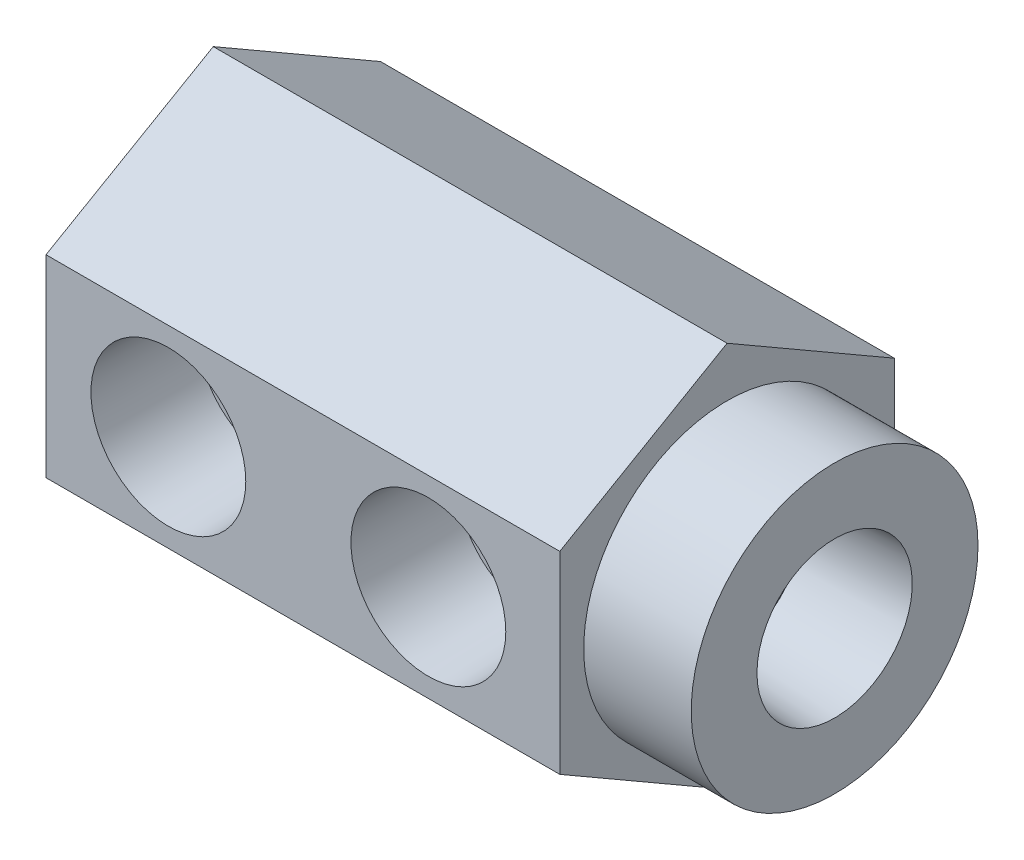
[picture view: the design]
ISO-10303-21;
HEADER;
FILE_DESCRIPTION(('STEP AP214'),'2;1');
FILE_NAME('part.step','',(''),(''),'','','');
FILE_SCHEMA(('AUTOMOTIVE_DESIGN { 1 0 10303 214 1 1 1 1 }'));
ENDSEC;
DATA;
#1=APPLICATION_CONTEXT('core data for automotive mechanical design processes');
#2=APPLICATION_PROTOCOL_DEFINITION('international standard','automotive_design',2000,#1);
#3=PRODUCT_CONTEXT('',#1,'mechanical');
#4=PRODUCT('Part','Part','',(#3));
#5=PRODUCT_RELATED_PRODUCT_CATEGORY('part','',(#4));
#6=PRODUCT_DEFINITION_FORMATION('','',#4);
#7=PRODUCT_DEFINITION_CONTEXT('part definition',#1,'design');
#8=PRODUCT_DEFINITION('design','',#6,#7);
#9=PRODUCT_DEFINITION_SHAPE('','',#8);
#10=(LENGTH_UNIT() NAMED_UNIT(*) SI_UNIT(.MILLI.,.METRE.));
#11=(NAMED_UNIT(*) PLANE_ANGLE_UNIT() SI_UNIT($,.RADIAN.));
#12=(NAMED_UNIT(*) SI_UNIT($,.STERADIAN.) SOLID_ANGLE_UNIT());
#13=UNCERTAINTY_MEASURE_WITH_UNIT(LENGTH_MEASURE(1.E-05),#10,'distance_accuracy_value','');
#14=(GEOMETRIC_REPRESENTATION_CONTEXT(3) GLOBAL_UNCERTAINTY_ASSIGNED_CONTEXT((#13)) GLOBAL_UNIT_ASSIGNED_CONTEXT((#10,
#11,#12)) REPRESENTATION_CONTEXT('',''));
#15=CARTESIAN_POINT('',(0.,0.,0.));
#16=DIRECTION('',(0.,0.,1.));
#17=DIRECTION('',(1.,0.,0.));
#18=AXIS2_PLACEMENT_3D('',#15,#16,#17);
#19=CARTESIAN_POINT('',(25.4,0.,0.));
#20=DIRECTION('',(1.,0.,0.));
#21=DIRECTION('',(0.,0.,-1.));
#22=AXIS2_PLACEMENT_3D('',#19,#20,#21);
#23=PLANE('',#22);
#24=DIRECTION('',(0.,0.,1.));
#25=VECTOR('',#24,1.);
#26=CARTESIAN_POINT('',(25.4,4.2164,11.1125));
#27=LINE('',#26,#25);
#28=CARTESIAN_POINT('',(25.4,4.2164,-1.14384635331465));
#29=VERTEX_POINT('',#28);
#30=CARTESIAN_POINT('',(25.4,4.2164,1.14384635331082));
#31=VERTEX_POINT('',#30);
#32=EDGE_CURVE('E247',#29,#31,#27,.T.);
#33=ORIENTED_EDGE('',*,*,#32,.F.);
#34=CARTESIAN_POINT('',(25.4,0.,0.));
#35=DIRECTION('',(-1.,0.,0.));
#36=DIRECTION('',(0.,0.,1.));
#37=AXIS2_PLACEMENT_3D('',#34,#35,#36);
#38=CIRCLE('',#37,4.36879999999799);
#39=EDGE_CURVE('E286',#31,#29,#38,.T.);
#40=ORIENTED_EDGE('',*,*,#39,.F.);
#41=EDGE_LOOP('',(#33,#40));
#42=FACE_BOUND('',#41,.T.);
#43=ADVANCED_FACE('F34',(#42),#23,.T.);
#44=CARTESIAN_POINT('',(41.275,0.,0.));
#45=DIRECTION('',(1.,0.,0.));
#46=DIRECTION('',(0.,0.,-1.));
#47=AXIS2_PLACEMENT_3D('',#44,#45,#46);
#48=PLANE('',#47);
#49=CARTESIAN_POINT('',(41.275,0.,0.));
#50=DIRECTION('',(1.,0.,0.));
#51=DIRECTION('',(0.,0.,-1.));
#52=AXIS2_PLACEMENT_3D('',#49,#50,#51);
#53=CIRCLE('',#52,9.525);
#54=CARTESIAN_POINT('',(41.275,0.,-9.525));
#55=VERTEX_POINT('',#54);
#56=EDGE_CURVE('E297',#55,#55,#53,.T.);
#57=ORIENTED_EDGE('',*,*,#56,.T.);
#58=EDGE_LOOP('',(#57));
#59=FACE_BOUND('',#58,.T.);
#60=CARTESIAN_POINT('',(41.275,0.,0.));
#61=DIRECTION('',(-1.,0.,0.));
#62=DIRECTION('',(0.,0.,1.));
#63=AXIS2_PLACEMENT_3D('',#60,#61,#62);
#64=CIRCLE('',#63,5.15886231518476);
#65=CARTESIAN_POINT('',(41.275,0.,5.15886231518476));
#66=VERTEX_POINT('',#65);
#67=EDGE_CURVE('E294',#66,#66,#64,.T.);
#68=ORIENTED_EDGE('',*,*,#67,.T.);
#69=EDGE_LOOP('',(#68));
#70=FACE_BOUND('',#69,.T.);
#71=ADVANCED_FACE('F320',(#59,#70),#48,.T.);
#72=CARTESIAN_POINT('',(34.13125,6.41580486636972,11.1125));
#73=DIRECTION('',(1.,0.,0.));
#74=DIRECTION('',(0.,0.,-1.));
#75=AXIS2_PLACEMENT_3D('',#72,#73,#74);
#76=PLANE('',#75);
#77=DIRECTION('',(0.,-0.5,0.866025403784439));
#78=VECTOR('',#77,1.);
#79=CARTESIAN_POINT('',(34.13125,12.8316097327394,0.));
#80=LINE('',#79,#78);
#81=CARTESIAN_POINT('',(34.13125,12.8316097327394,0.));
#82=VERTEX_POINT('',#81);
#83=CARTESIAN_POINT('',(34.13125,6.41580486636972,11.1125));
#84=VERTEX_POINT('',#83);
#85=EDGE_CURVE('E151',#82,#84,#80,.T.);
#86=ORIENTED_EDGE('',*,*,#85,.T.);
#87=DIRECTION('',(0.,-1.,0.));
#88=VECTOR('',#87,1.);
#89=CARTESIAN_POINT('',(34.13125,6.41580486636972,11.1125));
#90=LINE('',#89,#88);
#91=CARTESIAN_POINT('',(34.13125,-6.41580486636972,11.1125));
#92=VERTEX_POINT('',#91);
#93=EDGE_CURVE('E101',#84,#92,#90,.T.);
#94=ORIENTED_EDGE('',*,*,#93,.T.);
#95=DIRECTION('',(0.,-0.5,-0.866025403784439));
#96=VECTOR('',#95,1.);
#97=CARTESIAN_POINT('',(34.13125,-6.41580486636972,11.1125));
#98=LINE('',#97,#96);
#99=CARTESIAN_POINT('',(34.13125,-12.8316097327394,0.));
#100=VERTEX_POINT('',#99);
#101=EDGE_CURVE('E118',#92,#100,#98,.T.);
#102=ORIENTED_EDGE('',*,*,#101,.T.);
#103=DIRECTION('',(0.,0.5,-0.866025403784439));
#104=VECTOR('',#103,1.);
#105=CARTESIAN_POINT('',(34.13125,-12.8316097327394,0.));
#106=LINE('',#105,#104);
#107=CARTESIAN_POINT('',(34.13125,-6.41580486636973,-11.1125));
#108=VERTEX_POINT('',#107);
#109=EDGE_CURVE('E110',#100,#108,#106,.T.);
#110=ORIENTED_EDGE('',*,*,#109,.T.);
#111=DIRECTION('',(0.,1.,0.));
#112=VECTOR('',#111,1.);
#113=CARTESIAN_POINT('',(34.13125,-6.41580486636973,-11.1125));
#114=LINE('',#113,#112);
#115=CARTESIAN_POINT('',(34.13125,6.41580486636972,-11.1125));
#116=VERTEX_POINT('',#115);
#117=EDGE_CURVE('E115',#108,#116,#114,.T.);
#118=ORIENTED_EDGE('',*,*,#117,.T.);
#119=DIRECTION('',(0.,0.5,0.866025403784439));
#120=VECTOR('',#119,1.);
#121=CARTESIAN_POINT('',(34.13125,6.41580486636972,-11.1125));
#122=LINE('',#121,#120);
#123=EDGE_CURVE('E65',#116,#82,#122,.T.);
#124=ORIENTED_EDGE('',*,*,#123,.T.);
#125=EDGE_LOOP('',(#86,#94,#102,#110,#118,#124));
#126=FACE_BOUND('',#125,.T.);
#127=CARTESIAN_POINT('',(34.13125,0.,0.));
#128=DIRECTION('',(1.,0.,0.));
#129=DIRECTION('',(0.,0.,-1.));
#130=AXIS2_PLACEMENT_3D('',#127,#128,#129);
#131=CIRCLE('',#130,9.525);
#132=CARTESIAN_POINT('',(34.13125,0.,-9.525));
#133=VERTEX_POINT('',#132);
#134=EDGE_CURVE('E143',#133,#133,#131,.F.);
#135=ORIENTED_EDGE('',*,*,#134,.T.);
#136=EDGE_LOOP('',(#135));
#137=FACE_BOUND('',#136,.T.);
#138=ADVANCED_FACE('F112',(#126,#137),#76,.T.);
#139=CARTESIAN_POINT('',(34.13125,12.8316097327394,0.));
#140=DIRECTION('',(0.,-0.866025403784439,-0.5));
#141=DIRECTION('',(0.,0.5,-0.866025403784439));
#142=AXIS2_PLACEMENT_3D('',#139,#140,#141);
#143=PLANE('',#142);
#144=DIRECTION('',(0.,-0.5,0.866025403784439));
#145=VECTOR('',#144,1.);
#146=CARTESIAN_POINT('',(0.,12.8316097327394,0.));
#147=LINE('',#146,#145);
#148=CARTESIAN_POINT('',(0.,12.8316097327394,0.));
#149=VERTEX_POINT('',#148);
#150=CARTESIAN_POINT('',(0.,6.41580486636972,11.1125));
#151=VERTEX_POINT('',#150);
#152=EDGE_CURVE('E139',#149,#151,#147,.T.);
#153=ORIENTED_EDGE('',*,*,#152,.T.);
#154=DIRECTION('',(-1.,0.,0.));
#155=VECTOR('',#154,1.);
#156=CARTESIAN_POINT('',(34.13125,6.41580486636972,11.1125));
#157=LINE('',#156,#155);
#158=EDGE_CURVE('E158',#84,#151,#157,.T.);
#159=ORIENTED_EDGE('',*,*,#158,.F.);
#160=ORIENTED_EDGE('',*,*,#85,.F.);
#161=DIRECTION('',(-1.,0.,0.));
#162=VECTOR('',#161,1.);
#163=CARTESIAN_POINT('',(34.13125,12.8316097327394,0.));
#164=LINE('',#163,#162);
#165=EDGE_CURVE('E135',#82,#149,#164,.T.);
#166=ORIENTED_EDGE('',*,*,#165,.T.);
#167=EDGE_LOOP('',(#153,#159,#160,#166));
#168=FACE_BOUND('',#167,.T.);
#169=ADVANCED_FACE('F36',(#168),#143,.F.);
#170=CARTESIAN_POINT('',(34.13125,6.41580486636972,11.1125));
#171=DIRECTION('',(0.,0.,-1.));
#172=DIRECTION('',(0.,1.,0.));
#173=AXIS2_PLACEMENT_3D('',#170,#171,#172);
#174=PLANE('',#173);
#175=CARTESIAN_POINT('',(8.128,0.,11.1125));
#176=DIRECTION('',(0.,0.,1.));
#177=DIRECTION('',(1.,0.,0.));
#178=AXIS2_PLACEMENT_3D('',#175,#176,#177);
#179=CIRCLE('',#178,5.1435);
#180=CARTESIAN_POINT('',(13.2715,0.,11.1125));
#181=VERTEX_POINT('',#180);
#182=EDGE_CURVE('E562',#181,#181,#179,.T.);
#183=ORIENTED_EDGE('',*,*,#182,.F.);
#184=EDGE_LOOP('',(#183));
#185=FACE_BOUND('',#184,.T.);
#186=CARTESIAN_POINT('',(25.4,0.,11.1125));
#187=DIRECTION('',(0.,0.,1.));
#188=DIRECTION('',(1.,0.,0.));
#189=AXIS2_PLACEMENT_3D('',#186,#187,#188);
#190=CIRCLE('',#189,5.1435);
#191=CARTESIAN_POINT('',(30.5435,0.,11.1125));
#192=VERTEX_POINT('',#191);
#193=EDGE_CURVE('E263',#192,#192,#190,.T.);
#194=ORIENTED_EDGE('',*,*,#193,.F.);
#195=EDGE_LOOP('',(#194));
#196=FACE_BOUND('',#195,.T.);
#197=DIRECTION('',(0.,-1.,0.));
#198=VECTOR('',#197,1.);
#199=CARTESIAN_POINT('',(0.,6.41580486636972,11.1125));
#200=LINE('',#199,#198);
#201=CARTESIAN_POINT('',(0.,-6.41580486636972,11.1125));
#202=VERTEX_POINT('',#201);
#203=EDGE_CURVE('E142',#151,#202,#200,.T.);
#204=ORIENTED_EDGE('',*,*,#203,.T.);
#205=DIRECTION('',(-1.,0.,0.));
#206=VECTOR('',#205,1.);
#207=CARTESIAN_POINT('',(34.13125,-6.41580486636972,11.1125));
#208=LINE('',#207,#206);
#209=EDGE_CURVE('E155',#92,#202,#208,.T.);
#210=ORIENTED_EDGE('',*,*,#209,.F.);
#211=ORIENTED_EDGE('',*,*,#93,.F.);
#212=ORIENTED_EDGE('',*,*,#158,.T.);
#213=EDGE_LOOP('',(#204,#210,#211,#212));
#214=FACE_BOUND('',#213,.T.);
#215=ADVANCED_FACE('F305',(#185,#196,#214),#174,.F.);
#216=CARTESIAN_POINT('',(34.13125,-6.41580486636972,11.1125));
#217=DIRECTION('',(0.,0.866025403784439,-0.5));
#218=DIRECTION('',(0.,0.5,0.866025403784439));
#219=AXIS2_PLACEMENT_3D('',#216,#217,#218);
#220=PLANE('',#219);
#221=DIRECTION('',(0.,-0.5,-0.866025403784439));
#222=VECTOR('',#221,1.);
#223=CARTESIAN_POINT('',(0.,-6.41580486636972,11.1125));
#224=LINE('',#223,#222);
#225=CARTESIAN_POINT('',(0.,-12.8316097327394,0.));
#226=VERTEX_POINT('',#225);
#227=EDGE_CURVE('E145',#202,#226,#224,.T.);
#228=ORIENTED_EDGE('',*,*,#227,.T.);
#229=DIRECTION('',(-1.,0.,0.));
#230=VECTOR('',#229,1.);
#231=CARTESIAN_POINT('',(34.13125,-12.8316097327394,0.));
#232=LINE('',#231,#230);
#233=EDGE_CURVE('E130',#100,#226,#232,.T.);
#234=ORIENTED_EDGE('',*,*,#233,.F.);
#235=ORIENTED_EDGE('',*,*,#101,.F.);
#236=ORIENTED_EDGE('',*,*,#209,.T.);
#237=EDGE_LOOP('',(#228,#234,#235,#236));
#238=FACE_BOUND('',#237,.T.);
#239=ADVANCED_FACE('F308',(#238),#220,.F.);
#240=CARTESIAN_POINT('',(34.13125,-12.8316097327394,0.));
#241=DIRECTION('',(0.,0.866025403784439,0.5));
#242=DIRECTION('',(0.,-0.5,0.866025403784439));
#243=AXIS2_PLACEMENT_3D('',#240,#241,#242);
#244=PLANE('',#243);
#245=DIRECTION('',(0.,0.5,-0.866025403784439));
#246=VECTOR('',#245,1.);
#247=CARTESIAN_POINT('',(0.,-12.8316097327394,0.));
#248=LINE('',#247,#246);
#249=CARTESIAN_POINT('',(0.,-6.41580486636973,-11.1125));
#250=VERTEX_POINT('',#249);
#251=EDGE_CURVE('E127',#226,#250,#248,.T.);
#252=ORIENTED_EDGE('',*,*,#251,.T.);
#253=DIRECTION('',(-1.,0.,0.));
#254=VECTOR('',#253,1.);
#255=CARTESIAN_POINT('',(34.13125,-6.41580486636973,-11.1125));
#256=LINE('',#255,#254);
#257=EDGE_CURVE('E124',#108,#250,#256,.T.);
#258=ORIENTED_EDGE('',*,*,#257,.F.);
#259=ORIENTED_EDGE('',*,*,#109,.F.);
#260=ORIENTED_EDGE('',*,*,#233,.T.);
#261=EDGE_LOOP('',(#252,#258,#259,#260));
#262=FACE_BOUND('',#261,.T.);
#263=ADVANCED_FACE('F125',(#262),#244,.F.);
#264=CARTESIAN_POINT('',(34.13125,-6.41580486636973,-11.1125));
#265=DIRECTION('',(0.,0.,1.));
#266=DIRECTION('',(1.,0.,0.));
#267=AXIS2_PLACEMENT_3D('',#264,#265,#266);
#268=PLANE('',#267);
#269=CARTESIAN_POINT('',(8.128,0.,-11.1125));
#270=DIRECTION('',(0.,0.,-1.));
#271=DIRECTION('',(-1.,0.,0.));
#272=AXIS2_PLACEMENT_3D('',#269,#270,#271);
#273=CIRCLE('',#272,5.3164359);
#274=CARTESIAN_POINT('',(2.8115641,0.,-11.1125));
#275=VERTEX_POINT('',#274);
#276=EDGE_CURVE('E276',#275,#275,#273,.T.);
#277=ORIENTED_EDGE('',*,*,#276,.F.);
#278=EDGE_LOOP('',(#277));
#279=FACE_BOUND('',#278,.T.);
#280=DIRECTION('',(0.,1.,0.));
#281=VECTOR('',#280,1.);
#282=CARTESIAN_POINT('',(0.,-6.41580486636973,-11.1125));
#283=LINE('',#282,#281);
#284=CARTESIAN_POINT('',(0.,6.41580486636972,-11.1125));
#285=VERTEX_POINT('',#284);
#286=EDGE_CURVE('E148',#250,#285,#283,.T.);
#287=ORIENTED_EDGE('',*,*,#286,.T.);
#288=DIRECTION('',(-1.,0.,0.));
#289=VECTOR('',#288,1.);
#290=CARTESIAN_POINT('',(34.13125,6.41580486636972,-11.1125));
#291=LINE('',#290,#289);
#292=EDGE_CURVE('E131',#116,#285,#291,.T.);
#293=ORIENTED_EDGE('',*,*,#292,.F.);
#294=ORIENTED_EDGE('',*,*,#117,.F.);
#295=ORIENTED_EDGE('',*,*,#257,.T.);
#296=EDGE_LOOP('',(#287,#293,#294,#295));
#297=FACE_BOUND('',#296,.T.);
#298=ADVANCED_FACE('F133',(#279,#297),#268,.F.);
#299=CARTESIAN_POINT('',(34.13125,6.41580486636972,-11.1125));
#300=DIRECTION('',(0.,-0.866025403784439,0.5));
#301=DIRECTION('',(0.,-0.5,-0.866025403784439));
#302=AXIS2_PLACEMENT_3D('',#299,#300,#301);
#303=PLANE('',#302);
#304=DIRECTION('',(0.,0.5,0.866025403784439));
#305=VECTOR('',#304,1.);
#306=CARTESIAN_POINT('',(0.,6.41580486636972,-11.1125));
#307=LINE('',#306,#305);
#308=EDGE_CURVE('E92',#285,#149,#307,.T.);
#309=ORIENTED_EDGE('',*,*,#308,.T.);
#310=ORIENTED_EDGE('',*,*,#165,.F.);
#311=ORIENTED_EDGE('',*,*,#123,.F.);
#312=ORIENTED_EDGE('',*,*,#292,.T.);
#313=EDGE_LOOP('',(#309,#310,#311,#312));
#314=FACE_BOUND('',#313,.T.);
#315=ADVANCED_FACE('F312',(#314),#303,.F.);
#316=CARTESIAN_POINT('',(0.,6.41580486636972,11.1125));
#317=DIRECTION('',(1.,0.,0.));
#318=DIRECTION('',(0.,0.,-1.));
#319=AXIS2_PLACEMENT_3D('',#316,#317,#318);
#320=PLANE('',#319);
#321=ORIENTED_EDGE('',*,*,#152,.F.);
#322=ORIENTED_EDGE('',*,*,#308,.F.);
#323=ORIENTED_EDGE('',*,*,#286,.F.);
#324=ORIENTED_EDGE('',*,*,#251,.F.);
#325=ORIENTED_EDGE('',*,*,#227,.F.);
#326=ORIENTED_EDGE('',*,*,#203,.F.);
#327=EDGE_LOOP('',(#321,#322,#323,#324,#325,#326));
#328=FACE_BOUND('',#327,.T.);
#329=ADVANCED_FACE('F311',(#328),#320,.F.);
#330=CARTESIAN_POINT('',(41.275,0.,0.));
#331=DIRECTION('',(-1.,0.,0.));
#332=DIRECTION('',(0.,0.,1.));
#333=AXIS2_PLACEMENT_3D('',#330,#331,#332);
#334=CYLINDRICAL_SURFACE('',#333,9.525);
#335=ORIENTED_EDGE('',*,*,#134,.F.);
#336=EDGE_LOOP('',(#335));
#337=FACE_BOUND('',#336,.T.);
#338=ORIENTED_EDGE('',*,*,#56,.F.);
#339=EDGE_LOOP('',(#338));
#340=FACE_BOUND('',#339,.T.);
#341=ADVANCED_FACE('F412',(#337,#340),#334,.T.);
#342=CARTESIAN_POINT('',(41.275,0.,0.));
#343=DIRECTION('',(1.,0.,0.));
#344=DIRECTION('',(0.,0.,-1.));
#345=AXIS2_PLACEMENT_3D('',#342,#343,#344);
#346=CONICAL_SURFACE('',#345,5.15886231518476,0.0523598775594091);
#347=CARTESIAN_POINT('',(34.29,0.,0.));
#348=DIRECTION('',(-1.,0.,0.));
#349=DIRECTION('',(0.,0.,1.));
#350=AXIS2_PLACEMENT_3D('',#347,#348,#349);
#351=CIRCLE('',#350,4.79279397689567);
#352=CARTESIAN_POINT('',(34.29,0.,4.79279397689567));
#353=VERTEX_POINT('',#352);
#354=EDGE_CURVE('E291',#353,#353,#351,.T.);
#355=ORIENTED_EDGE('',*,*,#354,.T.);
#356=EDGE_LOOP('',(#355));
#357=FACE_BOUND('',#356,.T.);
#358=ORIENTED_EDGE('',*,*,#67,.F.);
#359=EDGE_LOOP('',(#358));
#360=FACE_BOUND('',#359,.T.);
#361=ADVANCED_FACE('F419',(#357,#360),#346,.F.);
#362=CARTESIAN_POINT('',(34.29,0.,-4.3688));
#363=DIRECTION('',(1.,0.,0.));
#364=DIRECTION('',(0.,0.,-1.));
#365=AXIS2_PLACEMENT_3D('',#362,#363,#364);
#366=PLANE('',#365);
#367=CARTESIAN_POINT('',(34.29,0.,0.));
#368=DIRECTION('',(-1.,0.,0.));
#369=DIRECTION('',(0.,0.,1.));
#370=AXIS2_PLACEMENT_3D('',#367,#368,#369);
#371=CIRCLE('',#370,4.3688);
#372=CARTESIAN_POINT('',(34.29,0.,4.3688));
#373=VERTEX_POINT('',#372);
#374=EDGE_CURVE('E288',#373,#373,#371,.T.);
#375=ORIENTED_EDGE('',*,*,#374,.T.);
#376=EDGE_LOOP('',(#375));
#377=FACE_BOUND('',#376,.T.);
#378=ORIENTED_EDGE('',*,*,#354,.F.);
#379=EDGE_LOOP('',(#378));
#380=FACE_BOUND('',#379,.T.);
#381=ADVANCED_FACE('F339',(#377,#380),#366,.T.);
#382=CARTESIAN_POINT('',(-4.01191983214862,0.,0.));
#383=DIRECTION('',(-1.,0.,0.));
#384=DIRECTION('',(0.,0.,1.));
#385=AXIS2_PLACEMENT_3D('',#382,#383,#384);
#386=CYLINDRICAL_SURFACE('',#385,4.36879999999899);
#387=CARTESIAN_POINT('',(25.4,-4.2164,-1.14384635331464));
#388=CARTESIAN_POINT('',(25.4382959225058,-4.21640509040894,-1.14380937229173));
#389=CARTESIAN_POINT('',(25.4765532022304,-4.21587815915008,-1.14577041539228));
#390=CARTESIAN_POINT('',(25.552565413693,-4.2138087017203,-1.15336705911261));
#391=CARTESIAN_POINT('',(25.5903214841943,-4.21226913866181,-1.15899193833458));
#392=CARTESIAN_POINT('',(25.7010377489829,-4.20628016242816,-1.18060825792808));
#393=CARTESIAN_POINT('',(25.7730026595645,-4.20045614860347,-1.20136776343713));
#394=CARTESIAN_POINT('',(25.9010959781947,-4.18692745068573,-1.24760620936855));
#395=CARTESIAN_POINT('',(25.9578264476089,-4.17971539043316,-1.27166887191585));
#396=CARTESIAN_POINT('',(26.0689520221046,-4.1633733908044,-1.32419771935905));
#397=CARTESIAN_POINT('',(26.1233452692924,-4.15424195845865,-1.35266732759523));
#398=CARTESIAN_POINT('',(26.284746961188,-4.12400027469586,-1.44328640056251));
#399=CARTESIAN_POINT('',(26.3886066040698,-4.10019771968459,-1.51007513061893));
#400=CARTESIAN_POINT('',(26.6094123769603,-4.04112930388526,-1.66240980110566));
#401=CARTESIAN_POINT('',(26.7251608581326,-4.004550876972,-1.74912466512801));
#402=CARTESIAN_POINT('',(26.950992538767,-3.92260860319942,-1.92589865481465));
#403=CARTESIAN_POINT('',(27.0610702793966,-3.87723648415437,-2.01596086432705));
#404=CARTESIAN_POINT('',(27.2761751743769,-3.77782789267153,-2.19659692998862));
#405=CARTESIAN_POINT('',(27.3812161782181,-3.72381718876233,-2.28716851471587));
#406=CARTESIAN_POINT('',(27.5868818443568,-3.60687682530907,-2.46746911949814));
#407=CARTESIAN_POINT('',(27.6875082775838,-3.5439507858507,-2.55719846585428));
#408=CARTESIAN_POINT('',(27.8839225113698,-3.40914667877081,-2.73431262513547));
#409=CARTESIAN_POINT('',(27.9797272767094,-3.3373036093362,-2.82170506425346));
#410=CARTESIAN_POINT('',(28.1664627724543,-3.18422748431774,-2.99338616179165));
#411=CARTESIAN_POINT('',(28.2573925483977,-3.10299259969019,-3.07767421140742));
#412=CARTESIAN_POINT('',(28.5217820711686,-2.8448347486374,-3.32412307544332));
#413=CARTESIAN_POINT('',(28.68722877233,-2.65319886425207,-3.4802217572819));
#414=CARTESIAN_POINT('',(28.946155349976,-2.28867585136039,-3.72591922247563));
#415=CARTESIAN_POINT('',(29.0468848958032,-2.12525740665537,-3.82197074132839));
#416=CARTESIAN_POINT('',(29.2280303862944,-1.77829965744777,-3.99518324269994));
#417=CARTESIAN_POINT('',(29.3084740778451,-1.59478833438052,-4.07237002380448));
#418=CARTESIAN_POINT('',(29.4335729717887,-1.24016971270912,-4.19259453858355));
#419=CARTESIAN_POINT('',(29.4818329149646,-1.07150882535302,-4.23906171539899));
#420=CARTESIAN_POINT('',(29.5573157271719,-0.725306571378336,-4.31179252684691));
#421=CARTESIAN_POINT('',(29.5845506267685,-0.547770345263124,-4.3380677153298));
#422=CARTESIAN_POINT('',(29.6160780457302,-0.188133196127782,-4.36848728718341));
#423=CARTESIAN_POINT('',(29.6202918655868,-0.00601875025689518,-4.37255575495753));
#424=CARTESIAN_POINT('',(29.6052294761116,0.356312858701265,-4.35801970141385));
#425=CARTESIAN_POINT('',(29.5859515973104,0.536529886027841,-4.33941356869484));
#426=CARTESIAN_POINT('',(29.5270019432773,0.880158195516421,-4.28257774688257));
#427=CARTESIAN_POINT('',(29.4884693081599,1.04395352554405,-4.24544432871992));
#428=CARTESIAN_POINT('',(29.3939743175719,1.36150296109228,-4.15452191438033));
#429=CARTESIAN_POINT('',(29.3380058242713,1.51525350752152,-4.10072705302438));
#430=CARTESIAN_POINT('',(29.1874242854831,1.86608787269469,-3.95630437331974));
#431=CARTESIAN_POINT('',(29.0861917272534,2.05776563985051,-3.85943081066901));
#432=CARTESIAN_POINT('',(28.8621173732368,2.41591223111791,-3.64602460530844));
#433=CARTESIAN_POINT('',(28.7392287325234,2.58232492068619,-3.52944936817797));
#434=CARTESIAN_POINT('',(28.4292865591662,2.94574331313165,-3.23746909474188));
#435=CARTESIAN_POINT('',(28.2351369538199,3.13191591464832,-3.05607279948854));
#436=CARTESIAN_POINT('',(27.9273645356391,3.37752954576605,-2.77386569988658));
#437=CARTESIAN_POINT('',(27.8219282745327,3.45383891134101,-2.67803363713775));
#438=CARTESIAN_POINT('',(27.6058304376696,3.59569760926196,-2.4843000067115));
#439=CARTESIAN_POINT('',(27.4951706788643,3.6612506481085,-2.38639916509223));
#440=CARTESIAN_POINT('',(27.3034156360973,3.76336891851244,-2.22032608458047));
#441=CARTESIAN_POINT('',(27.2236652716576,3.802657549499,-2.15224760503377));
#442=CARTESIAN_POINT('',(27.0614584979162,3.87627650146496,-2.01664021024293));
#443=CARTESIAN_POINT('',(26.9790024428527,3.91060746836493,-1.94911122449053));
#444=CARTESIAN_POINT('',(26.8108798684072,3.97436048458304,-1.81558453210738));
#445=CARTESIAN_POINT('',(26.7252107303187,4.00377841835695,-1.74958814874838));
#446=CARTESIAN_POINT('',(26.5499603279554,4.05758896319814,-1.62087320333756));
#447=CARTESIAN_POINT('',(26.4603817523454,4.08198496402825,-1.5581524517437));
#448=CARTESIAN_POINT('',(26.2863990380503,4.12303037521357,-1.44574995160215));
#449=CARTESIAN_POINT('',(26.2025707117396,4.14024606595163,-1.39539700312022));
#450=CARTESIAN_POINT('',(26.0299590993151,4.1699870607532,-1.30380280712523));
#451=CARTESIAN_POINT('',(25.9412226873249,4.18255009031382,-1.2624894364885));
#452=CARTESIAN_POINT('',(25.7781622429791,4.20001018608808,-1.20294863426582));
#453=CARTESIAN_POINT('',(25.705165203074,4.2060020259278,-1.18160521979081));
#454=CARTESIAN_POINT('',(25.592868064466,4.2121576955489,-1.15939760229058));
#455=CARTESIAN_POINT('',(25.554613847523,4.21373856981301,-1.15362350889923));
#456=CARTESIAN_POINT('',(25.4775866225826,4.2158639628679,-1.14582312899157));
#457=CARTESIAN_POINT('',(25.4388124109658,4.21640538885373,-1.14380802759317));
#458=CARTESIAN_POINT('',(25.3999999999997,4.21640000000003,-1.14384635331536));
#459=B_SPLINE_CURVE_WITH_KNOTS('',3,(#387,#388,#389,#390,#391,#392,#393,#394,#395,#396,#397,
#398,#399,#400,#401,#402,#403,#404,#405,#406,#407,#408,#409,#410,#411,#412,#413,#414,#415,#416,
#417,#418,#419,#420,#421,#422,#423,#424,#425,#426,#427,#428,#429,#430,#431,#432,#433,#434,#435,
#436,#437,#438,#439,#440,#441,#442,#443,#444,#445,#446,#447,#448,#449,#450,#451,#452,#453,#454,
#455,#456,#457,#458),.UNSPECIFIED.,.F.,.F.,(4,2,2,2,2,2,2,2,2,2,2,2,2,2,2,2,2,2,2,2,2,2,2,2,2,2,
2,2,2,2,2,2,2,2,2,4),(0.,0.114768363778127,0.229202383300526,0.453478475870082,
0.639361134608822,0.825388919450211,1.20188165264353,1.64896749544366,2.09647596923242,
2.54267362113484,2.98869061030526,3.43300933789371,3.87741474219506,4.76448895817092,
5.40626965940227,6.04716771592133,6.58930246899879,7.13112678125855,7.6748022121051,
8.21851628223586,8.73331387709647,9.24829289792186,9.95663818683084,10.6665349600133,
11.6342055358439,12.1187866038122,12.6032003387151,12.9390046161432,13.2747651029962,
13.6108054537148,13.9466182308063,14.2441145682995,14.539142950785,14.7669032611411,
14.8828759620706,14.9991932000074),.UNSPECIFIED.);
#460=CARTESIAN_POINT('',(25.4,-4.2164,-1.14384635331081));
#461=VERTEX_POINT('',#460);
#462=EDGE_CURVE('E11',#461,#29,#459,.T.);
#463=ORIENTED_EDGE('',*,*,#462,.F.);
#464=CARTESIAN_POINT('',(25.4,-4.2164,1.14384635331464));
#465=VERTEX_POINT('',#464);
#466=EDGE_CURVE('E285',#461,#465,#38,.T.);
#467=ORIENTED_EDGE('',*,*,#466,.T.);
#468=CARTESIAN_POINT('',(29.4292446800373,-1.24226256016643,4.18846));
#469=CARTESIAN_POINT('',(29.3952006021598,-1.35273289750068,4.15571214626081));
#470=CARTESIAN_POINT('',(29.3569523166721,-1.46061199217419,4.118946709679));
#471=CARTESIAN_POINT('',(29.2730241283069,-1.67045570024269,4.03838551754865));
#472=CARTESIAN_POINT('',(29.2273583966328,-1.77243109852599,3.99460317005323));
#473=CARTESIAN_POINT('',(29.1299690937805,-1.96908171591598,3.90139180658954));
#474=CARTESIAN_POINT('',(29.0783167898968,-2.06382425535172,3.85202936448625));
#475=CARTESIAN_POINT('',(28.9693395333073,-2.24704499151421,3.74810616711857));
#476=CARTESIAN_POINT('',(28.9120113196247,-2.33551953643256,3.69354242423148));
#477=CARTESIAN_POINT('',(28.7777414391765,-2.52699800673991,3.56608628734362));
#478=CARTESIAN_POINT('',(28.6994385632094,-2.6282408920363,3.49198149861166));
#479=CARTESIAN_POINT('',(28.5363557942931,-2.82085690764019,3.33831768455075));
#480=CARTESIAN_POINT('',(28.4515748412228,-2.91222841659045,3.25875776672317));
#481=CARTESIAN_POINT('',(28.275998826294,-3.08577014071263,3.09495512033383));
#482=CARTESIAN_POINT('',(28.1851741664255,-3.16788881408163,3.01068972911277));
#483=CARTESIAN_POINT('',(27.9986240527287,-3.32262985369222,2.83899583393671));
#484=CARTESIAN_POINT('',(27.9028992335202,-3.39525344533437,2.75156774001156));
#485=CARTESIAN_POINT('',(27.7047576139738,-3.532845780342,2.57263183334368));
#486=CARTESIAN_POINT('',(27.6022385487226,-3.59760480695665,2.4810764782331));
#487=CARTESIAN_POINT('',(27.3926047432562,-3.71781764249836,2.29702441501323));
#488=CARTESIAN_POINT('',(27.285488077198,-3.77326750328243,2.20452732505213));
#489=CARTESIAN_POINT('',(27.0666673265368,-3.87488965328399,2.02055799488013));
#490=CARTESIAN_POINT('',(26.9549765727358,-3.92108687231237,1.92908364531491));
#491=CARTESIAN_POINT('',(26.7257391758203,-4.00441579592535,1.74951137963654));
#492=CARTESIAN_POINT('',(26.6081985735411,-4.04155662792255,1.66141014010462));
#493=CARTESIAN_POINT('',(26.4005115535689,-4.09693829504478,1.51840665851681));
#494=CARTESIAN_POINT('',(26.3124794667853,-4.117524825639,1.46136281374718));
#495=CARTESIAN_POINT('',(26.1305999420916,-4.15365440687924,1.35523938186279));
#496=CARTESIAN_POINT('',(26.0367579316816,-4.16920208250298,1.30615251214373));
#497=CARTESIAN_POINT('',(25.8707386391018,-4.19060826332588,1.23537856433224));
#498=CARTESIAN_POINT('',(25.8004332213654,-4.19797337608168,1.20988515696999));
#499=CARTESIAN_POINT('',(25.6565333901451,-4.2091968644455,1.17027071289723));
#500=CARTESIAN_POINT('',(25.5829563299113,-4.21307185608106,1.1560958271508));
#501=CARTESIAN_POINT('',(25.4725911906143,-4.21593553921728,1.14554893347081));
#502=CARTESIAN_POINT('',(25.4363084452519,-4.21641147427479,1.14377318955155));
#503=CARTESIAN_POINT('',(25.4,-4.2164,1.14384635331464));
#504=B_SPLINE_CURVE_WITH_KNOTS('',3,(#468,#469,#470,#471,#472,#473,#474,#475,#476,#477,#478,
#479,#480,#481,#482,#483,#484,#485,#486,#487,#488,#489,#490,#491,#492,#493,#494,#495,#496,#497,
#498,#499,#500,#501,#502,#503),.UNSPECIFIED.,.F.,.F.,(4,2,2,2,2,2,2,2,2,2,2,2,2,2,2,2,2,4),(0.,
0.36013207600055,0.719584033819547,1.07512758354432,1.43087660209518,1.87390808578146,
2.31701222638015,2.7624738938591,3.20787801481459,3.66333295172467,4.11898056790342,
4.57338348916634,5.02732653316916,5.3477180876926,5.66781472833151,5.89257483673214,
6.11625914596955,6.22510746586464),.UNSPECIFIED.);
#505=CARTESIAN_POINT('',(29.4292446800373,-1.24226256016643,4.18846));
#506=VERTEX_POINT('',#505);
#507=EDGE_CURVE('E160',#506,#465,#504,.T.);
#508=ORIENTED_EDGE('',*,*,#507,.F.);
#509=DIRECTION('',(-1.,0.,0.));
#510=VECTOR('',#509,1.);
#511=CARTESIAN_POINT('',(-4.01191983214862,-1.24226256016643,4.18846));
#512=LINE('',#511,#510);
#513=CARTESIAN_POINT('',(30.177311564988,-1.24226256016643,4.18846));
#514=VERTEX_POINT('',#513);
#515=EDGE_CURVE('E168',#514,#506,#512,.T.);
#516=ORIENTED_EDGE('',*,*,#515,.F.);
#517=CARTESIAN_POINT('',(30.1771300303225,1.24293668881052,4.18826));
#518=CARTESIAN_POINT('',(30.200607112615,1.15583523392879,4.21412336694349));
#519=CARTESIAN_POINT('',(30.2217868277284,1.06732839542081,4.23741836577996));
#520=CARTESIAN_POINT('',(30.2592560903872,0.888007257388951,4.27858516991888));
#521=CARTESIAN_POINT('',(30.2755434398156,0.797191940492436,4.2964545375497));
#522=CARTESIAN_POINT('',(30.302904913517,0.613876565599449,4.32645329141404));
#523=CARTESIAN_POINT('',(30.313981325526,0.521377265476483,4.33858519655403));
#524=CARTESIAN_POINT('',(30.3307218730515,0.335324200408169,4.35691457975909));
#525=CARTESIAN_POINT('',(30.3363871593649,0.241770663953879,4.36311331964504));
#526=CARTESIAN_POINT('',(30.3422050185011,0.0540097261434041,4.36947895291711));
#527=CARTESIAN_POINT('',(30.3423413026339,-0.0401987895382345,4.36962802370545));
#528=CARTESIAN_POINT('',(30.3370571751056,-0.228273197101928,4.36384645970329));
#529=CARTESIAN_POINT('',(30.3316366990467,-0.322139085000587,4.35791575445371));
#530=CARTESIAN_POINT('',(30.3153617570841,-0.508659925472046,4.34009705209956));
#531=CARTESIAN_POINT('',(30.3045165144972,-0.601316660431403,4.32821916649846));
#532=CARTESIAN_POINT('',(30.2776075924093,-0.784900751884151,4.29871858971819));
#533=CARTESIAN_POINT('',(30.2615464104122,-0.875828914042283,4.28109864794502));
#534=CARTESIAN_POINT('',(30.2333463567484,-1.01252796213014,4.25011977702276));
#535=CARTESIAN_POINT('',(30.2229951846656,-1.05913454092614,4.23874207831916));
#536=CARTESIAN_POINT('',(30.2010123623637,-1.15159574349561,4.21456055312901));
#537=CARTESIAN_POINT('',(30.1893825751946,-1.19745135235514,4.2017588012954));
#538=CARTESIAN_POINT('',(30.1771300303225,-1.24293668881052,4.18826));
#539=B_SPLINE_CURVE_WITH_KNOTS('',3,(#517,#518,#519,#520,#521,#522,#523,#524,#525,#526,#527,
#528,#529,#530,#531,#532,#533,#534,#535,#536,#537,#538),.UNSPECIFIED.,.F.,.F.,(4,2,2,2,2,2,2,2,
2,2,4),(0.,0.28149265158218,0.563111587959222,0.844606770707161,1.12604207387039,
1.40830643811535,1.69057407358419,1.97236341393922,2.25401802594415,2.40121826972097,
2.54820680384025),.UNSPECIFIED.);
#540=CARTESIAN_POINT('',(30.177311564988,1.24226256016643,4.18846));
#541=VERTEX_POINT('',#540);
#542=EDGE_CURVE('E228',#541,#514,#539,.T.);
#543=ORIENTED_EDGE('',*,*,#542,.F.);
#544=DIRECTION('',(-1.,0.,0.));
#545=VECTOR('',#544,1.);
#546=CARTESIAN_POINT('',(-4.01191983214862,1.24226256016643,4.18846));
#547=LINE('',#546,#545);
#548=CARTESIAN_POINT('',(29.4292446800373,1.24226256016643,4.18846));
#549=VERTEX_POINT('',#548);
#550=EDGE_CURVE('E234',#549,#541,#547,.F.);
#551=ORIENTED_EDGE('',*,*,#550,.F.);
#552=CARTESIAN_POINT('',(25.4,4.2164,1.14384635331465));
#553=CARTESIAN_POINT('',(25.4382946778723,4.21640508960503,1.14380937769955));
#554=CARTESIAN_POINT('',(25.4765507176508,4.21587819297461,1.14577029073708));
#555=CARTESIAN_POINT('',(25.5525604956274,4.21380886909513,1.15336644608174));
#556=CARTESIAN_POINT('',(25.5903153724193,4.2122694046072,1.15899096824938));
#557=CARTESIAN_POINT('',(25.7010329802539,4.20628054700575,1.18060688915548));
#558=CARTESIAN_POINT('',(25.7730003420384,4.20045639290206,1.20136692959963));
#559=CARTESIAN_POINT('',(25.9010994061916,4.1869270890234,1.2476074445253));
#560=CARTESIAN_POINT('',(25.957833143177,4.17971453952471,1.27167170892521));
#561=CARTESIAN_POINT('',(26.0689649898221,4.16337135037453,1.32420417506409));
#562=CARTESIAN_POINT('',(26.1233612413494,4.15423921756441,1.35267580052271));
#563=CARTESIAN_POINT('',(26.2847590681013,4.12399749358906,1.44329421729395));
#564=CARTESIAN_POINT('',(26.3886125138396,4.10019613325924,1.51007919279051));
#565=CARTESIAN_POINT('',(26.6093729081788,4.04113986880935,1.66238258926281));
#566=CARTESIAN_POINT('',(26.7250845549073,4.00457500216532,1.74906763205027));
#567=CARTESIAN_POINT('',(26.9508454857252,3.92266551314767,1.92578088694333));
#568=CARTESIAN_POINT('',(27.0608893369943,3.87731265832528,2.01581216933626));
#569=CARTESIAN_POINT('',(27.2759989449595,3.77791674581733,2.19644572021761));
#570=CARTESIAN_POINT('',(27.3810754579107,3.72389369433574,2.28704622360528));
#571=CARTESIAN_POINT('',(27.5868141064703,3.60691884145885,2.4674086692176));
#572=CARTESIAN_POINT('',(27.6874779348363,3.5439705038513,2.55717092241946));
#573=CARTESIAN_POINT('',(27.8840648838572,3.40905006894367,2.73444118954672));
#574=CARTESIAN_POINT('',(27.9799999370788,3.33710249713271,2.82195457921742));
#575=CARTESIAN_POINT('',(28.1670159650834,3.18375149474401,2.99389591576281));
#576=CARTESIAN_POINT('',(28.258096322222,3.10234686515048,3.07832346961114));
#577=CARTESIAN_POINT('',(28.4343799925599,2.93013512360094,3.24265865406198));
#578=CARTESIAN_POINT('',(28.5196042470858,2.83936476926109,3.32258218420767));
#579=CARTESIAN_POINT('',(28.6836373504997,2.64794904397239,3.47705316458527));
#580=CARTESIAN_POINT('',(28.7624470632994,2.54730500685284,3.55160133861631));
#581=CARTESIAN_POINT('',(28.8989104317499,2.35518817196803,3.68108458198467));
#582=CARTESIAN_POINT('',(28.9578122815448,2.26534949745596,3.73712818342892));
#583=CARTESIAN_POINT('',(29.0697477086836,2.07912888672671,3.8438454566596));
#584=CARTESIAN_POINT('',(29.1227847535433,1.9827508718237,3.89452230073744));
#585=CARTESIAN_POINT('',(29.2226917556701,1.78260449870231,3.99013074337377));
#586=CARTESIAN_POINT('',(29.2694922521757,1.67877001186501,4.03499749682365));
#587=CARTESIAN_POINT('',(29.355411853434,1.46495258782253,4.11746606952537));
#588=CARTESIAN_POINT('',(29.3945155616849,1.35495788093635,4.15505332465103));
#589=CARTESIAN_POINT('',(29.4292446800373,1.24226256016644,4.18846));
#590=B_SPLINE_CURVE_WITH_KNOTS('',3,(#552,#553,#554,#555,#556,#557,#558,#559,#560,#561,#562,
#563,#564,#565,#566,#567,#568,#569,#570,#571,#572,#573,#574,#575,#576,#577,#578,#579,#580,#581,
#582,#583,#584,#585,#586,#587,#588,#589),.UNSPECIFIED.,.F.,.F.,(4,2,2,2,2,2,2,2,2,2,2,2,2,2,2,2,
2,2,4),(0.,0.114764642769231,0.229194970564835,0.453478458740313,0.639372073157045,
0.825410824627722,1.20188165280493,1.64882044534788,2.09617996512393,2.54252167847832,
2.98869064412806,3.43366913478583,3.8787041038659,4.32205448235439,4.76534505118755,
5.12845015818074,5.49133942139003,5.85798208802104,6.22535088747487),.UNSPECIFIED.);
#591=EDGE_CURVE('E48',#31,#549,#590,.T.);
#592=ORIENTED_EDGE('',*,*,#591,.F.);
#593=ORIENTED_EDGE('',*,*,#39,.T.);
#594=EDGE_LOOP('',(#463,#467,#508,#516,#543,#551,#592,#593));
#595=FACE_BOUND('',#594,.T.);
#596=ORIENTED_EDGE('',*,*,#374,.F.);
#597=EDGE_LOOP('',(#596));
#598=FACE_BOUND('',#597,.T.);
#599=ADVANCED_FACE('F170',(#595,#598),#386,.F.);
#600=DIRECTION('',(0.,0.,1.));
#601=VECTOR('',#600,1.);
#602=CARTESIAN_POINT('',(25.4,-4.2164,11.1125));
#603=LINE('',#602,#601);
#604=EDGE_CURVE('E272',#465,#461,#603,.F.);
#605=ORIENTED_EDGE('',*,*,#604,.F.);
#606=ORIENTED_EDGE('',*,*,#466,.F.);
#607=EDGE_LOOP('',(#605,#606));
#608=FACE_BOUND('',#607,.T.);
#609=ADVANCED_FACE('F324',(#608),#23,.T.);
#610=CARTESIAN_POINT('',(8.128,0.,-11.1125));
#611=DIRECTION('',(0.,0.,-1.));
#612=DIRECTION('',(-1.,0.,0.));
#613=AXIS2_PLACEMENT_3D('',#610,#611,#612);
#614=CYLINDRICAL_SURFACE('',#613,4.2164);
#615=CARTESIAN_POINT('',(12.3444,0.,-2.70509999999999));
#616=CARTESIAN_POINT('',(12.3443892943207,0.136794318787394,-2.70508836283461));
#617=CARTESIAN_POINT('',(12.3376743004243,0.273730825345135,-2.69465346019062));
#618=CARTESIAN_POINT('',(12.3114470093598,0.543355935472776,-2.65348953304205));
#619=CARTESIAN_POINT('',(12.2919137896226,0.676037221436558,-2.62272732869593));
#620=CARTESIAN_POINT('',(12.2420050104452,0.932743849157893,-2.54274340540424));
#621=CARTESIAN_POINT('',(12.2116834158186,1.05680866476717,-2.49361350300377));
#622=CARTESIAN_POINT('',(12.1426871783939,1.29446961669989,-2.3789376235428));
#623=CARTESIAN_POINT('',(12.1040129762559,1.40806630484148,-2.31339251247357));
#624=CARTESIAN_POINT('',(12.017711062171,1.63209650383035,-2.16184923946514));
#625=CARTESIAN_POINT('',(11.9696092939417,1.74150752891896,-2.0746149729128));
#626=CARTESIAN_POINT('',(11.8706383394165,1.94513101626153,-1.88505172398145));
#627=CARTESIAN_POINT('',(11.8197653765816,2.03932200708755,-1.78270180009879));
#628=CARTESIAN_POINT('',(11.7121621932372,2.22368074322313,-1.54858609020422));
#629=CARTESIAN_POINT('',(11.6556450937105,2.31131010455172,-1.41470676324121));
#630=CARTESIAN_POINT('',(11.5517355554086,2.46262148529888,-1.13084652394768));
#631=CARTESIAN_POINT('',(11.5043275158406,2.52634462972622,-0.980893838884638));
#632=CARTESIAN_POINT('',(11.4375031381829,2.61292228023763,-0.710314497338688));
#633=CARTESIAN_POINT('',(11.4139826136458,2.64217265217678,-0.592756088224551));
#634=CARTESIAN_POINT('',(11.3793294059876,2.68470892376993,-0.353075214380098));
#635=CARTESIAN_POINT('',(11.3681777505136,2.69801927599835,-0.230960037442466));
#636=CARTESIAN_POINT('',(11.3599599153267,2.7078617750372,0.0148253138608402));
#637=CARTESIAN_POINT('',(11.3629380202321,2.70434117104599,0.138499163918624));
#638=CARTESIAN_POINT('',(11.3825911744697,2.68064969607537,0.383168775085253));
#639=CARTESIAN_POINT('',(11.3992775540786,2.66046505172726,0.504162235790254));
#640=CARTESIAN_POINT('',(11.4431825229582,2.60552605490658,0.736649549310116));
#641=CARTESIAN_POINT('',(11.4700637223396,2.5712357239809,0.848320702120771));
#642=CARTESIAN_POINT('',(11.5313605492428,2.4895317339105,1.06450359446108));
#643=CARTESIAN_POINT('',(11.5657786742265,2.44211372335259,1.16901294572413));
#644=CARTESIAN_POINT('',(11.6463261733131,2.32494765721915,1.38947859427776));
#645=CARTESIAN_POINT('',(11.6934321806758,2.25265222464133,1.50372248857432));
#646=CARTESIAN_POINT('',(11.7897853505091,2.09239583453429,1.71975722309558));
#647=CARTESIAN_POINT('',(11.8390350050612,2.0044162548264,1.82153301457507));
#648=CARTESIAN_POINT('',(11.9447411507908,1.79625282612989,2.028894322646));
#649=CARTESIAN_POINT('',(12.0008543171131,1.67312206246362,2.13172898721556));
#650=CARTESIAN_POINT('',(12.1048110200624,1.40825264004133,2.31522436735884));
#651=CARTESIAN_POINT('',(12.1526633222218,1.26653398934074,2.39590864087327));
#652=CARTESIAN_POINT('',(12.2266538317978,0.997260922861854,2.51800549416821));
#653=CARTESIAN_POINT('',(12.2552158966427,0.872465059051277,2.56403196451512));
#654=CARTESIAN_POINT('',(12.3012565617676,0.615578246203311,2.63750542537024));
#655=CARTESIAN_POINT('',(12.3187441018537,0.483493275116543,2.66496740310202));
#656=CARTESIAN_POINT('',(12.341064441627,0.215161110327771,2.69993206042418));
#657=CARTESIAN_POINT('',(12.3458541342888,0.0789013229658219,2.70736675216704));
#658=CARTESIAN_POINT('',(12.3421737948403,-0.193010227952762,2.70162975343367));
#659=CARTESIAN_POINT('',(12.3337030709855,-0.328661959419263,2.68845698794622));
#660=CARTESIAN_POINT('',(12.3051447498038,-0.587868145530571,2.64354897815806));
#661=CARTESIAN_POINT('',(12.285710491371,-0.711680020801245,2.61285663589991));
#662=CARTESIAN_POINT('',(12.2373351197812,-0.952072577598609,2.53517127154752));
#663=CARTESIAN_POINT('',(12.2083924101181,-1.06865204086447,2.48817551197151));
#664=CARTESIAN_POINT('',(12.1406987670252,-1.30074982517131,2.37559707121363));
#665=CARTESIAN_POINT('',(12.1013831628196,-1.41555996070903,2.30890187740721));
#666=CARTESIAN_POINT('',(12.0171229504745,-1.63290087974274,2.16067870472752));
#667=CARTESIAN_POINT('',(11.9721740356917,-1.73542214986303,2.07913935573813));
#668=CARTESIAN_POINT('',(11.872671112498,-1.94177872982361,1.88934381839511));
#669=CARTESIAN_POINT('',(11.8177001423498,-2.0434122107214,1.77890853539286));
#670=CARTESIAN_POINT('',(11.7095763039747,-2.22749573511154,1.54217703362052));
#671=CARTESIAN_POINT('',(11.6564238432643,-2.30994150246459,1.41587728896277));
#672=CARTESIAN_POINT('',(11.5646198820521,-2.44404790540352,1.16680715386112));
#673=CARTESIAN_POINT('',(11.5249796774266,-2.49835271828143,1.04582945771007));
#674=CARTESIAN_POINT('',(11.4562432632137,-2.58922943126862,0.794489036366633));
#675=CARTESIAN_POINT('',(11.4271325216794,-2.62582579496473,0.66413954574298));
#676=CARTESIAN_POINT('',(11.3945873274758,-2.66603154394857,0.463244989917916));
#677=CARTESIAN_POINT('',(11.3855743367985,-2.67700414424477,0.394999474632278));
#678=CARTESIAN_POINT('',(11.3717760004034,-2.69370899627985,0.257460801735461));
#679=CARTESIAN_POINT('',(11.3669884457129,-2.69944398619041,0.188168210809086));
#680=CARTESIAN_POINT('',(11.3618934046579,-2.70554596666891,0.0492083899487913));
#681=CARTESIAN_POINT('',(11.3615840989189,-2.70591513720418,-0.020458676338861));
#682=CARTESIAN_POINT('',(11.3654455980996,-2.70129213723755,-0.159467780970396));
#683=CARTESIAN_POINT('',(11.3696160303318,-2.69630041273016,-0.228809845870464));
#684=CARTESIAN_POINT('',(11.386706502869,-2.67566338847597,-0.415102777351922));
#685=CARTESIAN_POINT('',(11.4037212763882,-2.65498950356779,-0.531169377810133));
#686=CARTESIAN_POINT('',(11.447974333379,-2.59942913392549,-0.757763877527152));
#687=CARTESIAN_POINT('',(11.4752228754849,-2.56452838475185,-0.868286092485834));
#688=CARTESIAN_POINT('',(11.5476328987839,-2.46757707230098,-1.11910830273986));
#689=CARTESIAN_POINT('',(11.5957314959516,-2.4003153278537,-1.25654844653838));
#690=CARTESIAN_POINT('',(11.6981904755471,-2.24508779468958,-1.51662555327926));
#691=CARTESIAN_POINT('',(11.7525592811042,-2.1570939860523,-1.63924213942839));
#692=CARTESIAN_POINT('',(11.8623415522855,-1.96099982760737,-1.8695426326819));
#693=CARTESIAN_POINT('',(11.917759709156,-1.85266980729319,-1.97702863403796));
#694=CARTESIAN_POINT('',(12.0237521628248,-1.61792424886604,-2.1733015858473));
#695=CARTESIAN_POINT('',(12.0743263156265,-1.49150817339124,-2.26208798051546));
#696=CARTESIAN_POINT('',(12.1436228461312,-1.28771957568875,-2.3802971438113));
#697=CARTESIAN_POINT('',(12.1659442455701,-1.21609453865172,-2.41769984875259));
#698=CARTESIAN_POINT('',(12.2073429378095,-1.06902354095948,-2.48622708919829));
#699=CARTESIAN_POINT('',(12.2264220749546,-0.993579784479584,-2.51735519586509));
#700=CARTESIAN_POINT('',(12.2607137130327,-0.839592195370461,-2.57280635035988));
#701=CARTESIAN_POINT('',(12.2759353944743,-0.761056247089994,-2.59714556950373));
#702=CARTESIAN_POINT('',(12.3020631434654,-0.60146207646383,-2.63867412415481));
#703=CARTESIAN_POINT('',(12.312972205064,-0.520405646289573,-2.65586842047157));
#704=CARTESIAN_POINT('',(12.3290848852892,-0.366306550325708,-2.6811816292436));
#705=CARTESIAN_POINT('',(12.3348122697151,-0.293455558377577,-2.69013590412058));
#706=CARTESIAN_POINT('',(12.3424727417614,-0.147083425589,-2.70209827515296));
#707=CARTESIAN_POINT('',(12.3444057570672,-0.0735622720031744,-2.70510625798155));
#708=CARTESIAN_POINT('',(12.3444,0.,-2.70509999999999));
#709=B_SPLINE_CURVE_WITH_KNOTS('',3,(#615,#616,#617,#618,#619,#620,#621,#622,#623,#624,#625,
#626,#627,#628,#629,#630,#631,#632,#633,#634,#635,#636,#637,#638,#639,#640,#641,#642,#643,#644,
#645,#646,#647,#648,#649,#650,#651,#652,#653,#654,#655,#656,#657,#658,#659,#660,#661,#662,#663,
#664,#665,#666,#667,#668,#669,#670,#671,#672,#673,#674,#675,#676,#677,#678,#679,#680,#681,#682,
#683,#684,#685,#686,#687,#688,#689,#690,#691,#692,#693,#694,#695,#696,#697,#698,#699,#700,#701,
#702,#703,#704,#705,#706,#707,#708),.UNSPECIFIED.,.T.,.F.,(4,2,2,2,2,2,2,2,2,2,2,2,2,2,2,2,2,2,
2,2,2,2,2,2,2,2,2,2,2,2,2,2,2,2,2,2,2,2,2,2,2,2,2,2,2,2,4),(0.,0.410088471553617,
0.820847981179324,1.22958105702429,1.63829257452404,2.08050495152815,2.52333582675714,
3.03001806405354,3.53582463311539,3.90452913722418,4.27266730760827,4.64196003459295,
5.01155829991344,5.36986350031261,5.72828761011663,6.15624349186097,6.58471092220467,
7.09209426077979,7.59893586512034,8.00533671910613,8.41140909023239,8.81885825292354,
9.22632867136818,9.61175253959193,9.9972411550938,10.4110716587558,10.8252204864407,
11.3027748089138,11.7804354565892,12.1941244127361,12.60724022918,12.8160795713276,
13.0248096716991,13.2334549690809,13.4420829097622,13.7977258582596,14.153726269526,
14.6323802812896,15.111684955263,15.5967696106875,16.0818686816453,16.3330368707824,
16.5840617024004,16.8344833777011,17.0847308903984,17.3052551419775,17.5257835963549),.UNSPECIFIED.);
#710=CARTESIAN_POINT('',(12.3444,0.,-2.70509999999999));
#711=VERTEX_POINT('',#710);
#712=EDGE_CURVE('E38',#711,#711,#709,.T.);
#713=ORIENTED_EDGE('',*,*,#712,.T.);
#714=EDGE_LOOP('',(#713));
#715=FACE_BOUND('',#714,.T.);
#716=CARTESIAN_POINT('',(8.128,0.,4.18846));
#717=DIRECTION('',(0.,0.,1.));
#718=DIRECTION('',(1.,0.,0.));
#719=AXIS2_PLACEMENT_3D('',#716,#717,#718);
#720=CIRCLE('',#719,4.2164);
#721=CARTESIAN_POINT('',(12.3444,0.,4.18846));
#722=VERTEX_POINT('',#721);
#723=EDGE_CURVE('E266',#722,#722,#720,.T.);
#724=ORIENTED_EDGE('',*,*,#723,.T.);
#725=EDGE_LOOP('',(#724));
#726=FACE_BOUND('',#725,.T.);
#727=CARTESIAN_POINT('',(8.128,0.,-4.18846));
#728=DIRECTION('',(0.,0.,-1.));
#729=DIRECTION('',(-1.,0.,0.));
#730=AXIS2_PLACEMENT_3D('',#727,#728,#729);
#731=CIRCLE('',#730,4.2164);
#732=CARTESIAN_POINT('',(3.9116,0.,-4.18846));
#733=VERTEX_POINT('',#732);
#734=EDGE_CURVE('E282',#733,#733,#731,.T.);
#735=ORIENTED_EDGE('',*,*,#734,.T.);
#736=EDGE_LOOP('',(#735));
#737=FACE_BOUND('',#736,.T.);
#738=ADVANCED_FACE('F331',(#715,#726,#737),#614,.F.);
#739=CARTESIAN_POINT('',(12.3444,0.,-4.18846));
#740=DIRECTION('',(0.,0.,1.));
#741=DIRECTION('',(1.,0.,0.));
#742=AXIS2_PLACEMENT_3D('',#739,#740,#741);
#743=PLANE('',#742);
#744=ORIENTED_EDGE('',*,*,#734,.F.);
#745=EDGE_LOOP('',(#744));
#746=FACE_BOUND('',#745,.T.);
#747=CARTESIAN_POINT('',(8.128,0.,-4.18846));
#748=DIRECTION('',(0.,0.,-1.));
#749=DIRECTION('',(-1.,0.,0.));
#750=AXIS2_PLACEMENT_3D('',#747,#748,#749);
#751=CIRCLE('',#750,5.10912086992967);
#752=CARTESIAN_POINT('',(3.01887913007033,0.,-4.18846));
#753=VERTEX_POINT('',#752);
#754=EDGE_CURVE('E279',#753,#753,#751,.T.);
#755=ORIENTED_EDGE('',*,*,#754,.T.);
#756=EDGE_LOOP('',(#755));
#757=FACE_BOUND('',#756,.T.);
#758=ADVANCED_FACE('F337',(#746,#757),#743,.F.);
#759=CARTESIAN_POINT('',(8.128,0.,-11.1125));
#760=DIRECTION('',(0.,0.,-1.));
#761=DIRECTION('',(-1.,0.,0.));
#762=AXIS2_PLACEMENT_3D('',#759,#760,#761);
#763=CONICAL_SURFACE('',#762,5.3164359,0.0299323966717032);
#764=ORIENTED_EDGE('',*,*,#754,.F.);
#765=EDGE_LOOP('',(#764));
#766=FACE_BOUND('',#765,.T.);
#767=ORIENTED_EDGE('',*,*,#276,.T.);
#768=EDGE_LOOP('',(#767));
#769=FACE_BOUND('',#768,.T.);
#770=ADVANCED_FACE('F354',(#766,#769),#763,.F.);
#771=CARTESIAN_POINT('',(25.4,0.,-4.7625));
#772=DIRECTION('',(0.,0.,1.));
#773=DIRECTION('',(1.,0.,0.));
#774=AXIS2_PLACEMENT_3D('',#771,#772,#773);
#775=CONICAL_SURFACE('',#774,4.2164,1.02974425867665);
#776=CARTESIAN_POINT('',(25.4,0.,-7.29596871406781));
#777=VERTEX_POINT('',#776);
#778=VERTEX_LOOP('',#777);
#779=FACE_BOUND('',#778,.T.);
#780=CARTESIAN_POINT('',(25.4,0.,-4.7625));
#781=DIRECTION('',(0.,0.,1.));
#782=DIRECTION('',(1.,0.,0.));
#783=AXIS2_PLACEMENT_3D('',#780,#781,#782);
#784=CIRCLE('',#783,4.2164);
#785=CARTESIAN_POINT('',(29.6164,0.,-4.7625));
#786=VERTEX_POINT('',#785);
#787=EDGE_CURVE('E256',#786,#786,#784,.T.);
#788=ORIENTED_EDGE('',*,*,#787,.T.);
#789=EDGE_LOOP('',(#788));
#790=FACE_BOUND('',#789,.T.);
#791=ADVANCED_FACE('F180',(#779,#790),#775,.F.);
#792=CARTESIAN_POINT('',(25.4,0.,11.1125));
#793=DIRECTION('',(0.,0.,1.));
#794=DIRECTION('',(1.,0.,0.));
#795=AXIS2_PLACEMENT_3D('',#792,#793,#794);
#796=CYLINDRICAL_SURFACE('',#795,4.2164);
#797=CARTESIAN_POINT('',(21.1836,0.,-3.17499999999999));
#798=CARTESIAN_POINT('',(21.1836006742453,-0.0774641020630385,-3.17499930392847));
#799=CARTESIAN_POINT('',(21.1857399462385,-0.154943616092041,-3.17215987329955));
#800=CARTESIAN_POINT('',(21.1942479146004,-0.309288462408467,-3.16084798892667));
#801=CARTESIAN_POINT('',(21.2006189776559,-0.386153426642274,-3.152372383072));
#802=CARTESIAN_POINT('',(21.2174572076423,-0.538762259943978,-3.12990674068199));
#803=CARTESIAN_POINT('',(21.227931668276,-0.61450388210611,-3.11590688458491));
#804=CARTESIAN_POINT('',(21.2527332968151,-0.764184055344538,-3.08261871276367));
#805=CARTESIAN_POINT('',(21.2670621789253,-0.838121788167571,-3.06332804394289));
#806=CARTESIAN_POINT('',(21.3151804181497,-1.05553069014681,-2.99820207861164));
#807=CARTESIAN_POINT('',(21.3542300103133,-1.19570317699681,-2.94494457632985));
#808=CARTESIAN_POINT('',(21.4434245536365,-1.46410571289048,-2.82115606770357));
#809=CARTESIAN_POINT('',(21.4935667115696,-1.59233875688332,-2.75062940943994));
#810=CARTESIAN_POINT('',(21.6068261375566,-1.84689314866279,-2.5873817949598));
#811=CARTESIAN_POINT('',(21.6707156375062,-1.97193306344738,-2.4932086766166));
#812=CARTESIAN_POINT('',(21.803919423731,-2.20552362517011,-2.28919194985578));
#813=CARTESIAN_POINT('',(21.8732419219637,-2.31404855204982,-2.17932440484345));
#814=CARTESIAN_POINT('',(21.9850069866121,-2.47411716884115,-1.9919714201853));
#815=CARTESIAN_POINT('',(22.0271898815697,-2.53117256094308,-1.91895643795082));
#816=CARTESIAN_POINT('',(22.1107963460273,-2.63890367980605,-1.76788661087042));
#817=CARTESIAN_POINT('',(22.1522196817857,-2.68957746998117,-1.68983024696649));
#818=CARTESIAN_POINT('',(22.2329835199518,-2.78422357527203,-1.52886547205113));
#819=CARTESIAN_POINT('',(22.2723264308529,-2.82820375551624,-1.44596291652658));
#820=CARTESIAN_POINT('',(22.3474787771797,-2.90915697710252,-1.2752852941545));
#821=CARTESIAN_POINT('',(22.3832887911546,-2.9461311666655,-1.18751102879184));
#822=CARTESIAN_POINT('',(22.459842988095,-3.02279202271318,-0.979359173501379));
#823=CARTESIAN_POINT('',(22.4987123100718,-3.05980953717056,-0.857263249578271));
#824=CARTESIAN_POINT('',(22.5626927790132,-3.11923926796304,-0.606244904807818));
#825=CARTESIAN_POINT('',(22.5878355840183,-3.14168511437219,-0.477338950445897));
#826=CARTESIAN_POINT('',(22.6204030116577,-3.17055070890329,-0.214166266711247));
#827=CARTESIAN_POINT('',(22.6276621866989,-3.1768208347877,-0.0798610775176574));
#828=CARTESIAN_POINT('',(22.6224432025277,-3.17225670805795,0.188093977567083));
#829=CARTESIAN_POINT('',(22.6099586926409,-3.16141695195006,0.321743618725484));
#830=CARTESIAN_POINT('',(22.5701185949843,-3.12576103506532,0.569373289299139));
#831=CARTESIAN_POINT('',(22.5445432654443,-3.10260728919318,0.683903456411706));
#832=CARTESIAN_POINT('',(22.4830224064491,-3.04484078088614,0.907128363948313));
#833=CARTESIAN_POINT('',(22.4470667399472,-3.01021681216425,1.01581727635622));
#834=CARTESIAN_POINT('',(22.3431977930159,-2.90555725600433,1.29312267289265));
#835=CARTESIAN_POINT('',(22.269429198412,-2.82695902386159,1.45631350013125));
#836=CARTESIAN_POINT('',(22.1145426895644,-2.64539874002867,1.76483550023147));
#837=CARTESIAN_POINT('',(22.0334070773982,-2.54237700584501,1.91012157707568));
#838=CARTESIAN_POINT('',(21.8699489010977,-2.31029566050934,2.18549658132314));
#839=CARTESIAN_POINT('',(21.7876510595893,-2.1806237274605,2.31508667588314));
#840=CARTESIAN_POINT('',(21.6315150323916,-1.89802886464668,2.55185214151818));
#841=CARTESIAN_POINT('',(21.5576609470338,-1.74515093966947,2.65906996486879));
#842=CARTESIAN_POINT('',(21.4383733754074,-1.45038304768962,2.8284116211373));
#843=CARTESIAN_POINT('',(21.3902080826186,-1.31231662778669,2.89526100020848));
#844=CARTESIAN_POINT('',(21.3071898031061,-1.02433802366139,3.00919030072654));
#845=CARTESIAN_POINT('',(21.2723285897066,-0.874433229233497,3.05628244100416));
#846=CARTESIAN_POINT('',(21.2321936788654,-0.643155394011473,3.11019935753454));
#847=CARTESIAN_POINT('',(21.220822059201,-0.564686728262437,3.12540994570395));
#848=CARTESIAN_POINT('',(21.2024703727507,-0.406336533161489,3.1499078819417));
#849=CARTESIAN_POINT('',(21.1954882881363,-0.326455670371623,3.15919795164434));
#850=CARTESIAN_POINT('',(21.186100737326,-0.165959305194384,3.17168093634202));
#851=CARTESIAN_POINT('',(21.1836946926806,-0.085343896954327,3.17487462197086));
#852=CARTESIAN_POINT('',(21.1835106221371,0.0758763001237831,3.17511831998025));
#853=CARTESIAN_POINT('',(21.1857322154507,0.156481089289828,3.17216883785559));
#854=CARTESIAN_POINT('',(21.1983545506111,0.380647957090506,3.15539030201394));
#855=CARTESIAN_POINT('',(21.213840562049,0.523499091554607,3.13479352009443));
#856=CARTESIAN_POINT('',(21.2583399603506,0.802976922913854,3.07511480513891));
#857=CARTESIAN_POINT('',(21.2873561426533,0.939602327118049,3.03602905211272));
#858=CARTESIAN_POINT('',(21.3579336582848,1.20814931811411,2.93972896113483));
#859=CARTESIAN_POINT('',(21.3998733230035,1.33977210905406,2.88196488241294));
#860=CARTESIAN_POINT('',(21.4931482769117,1.5914065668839,2.75103534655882));
#861=CARTESIAN_POINT('',(21.544484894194,1.71141658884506,2.67786771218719));
#862=CARTESIAN_POINT('',(21.6627612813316,1.95773092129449,2.50483373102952));
#863=CARTESIAN_POINT('',(21.7308761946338,2.08176504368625,2.40255103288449));
#864=CARTESIAN_POINT('',(21.8715011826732,2.31213350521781,2.18178706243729));
#865=CARTESIAN_POINT('',(21.9440205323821,2.41842859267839,2.06327089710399));
#866=CARTESIAN_POINT('',(22.0590846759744,2.57323301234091,1.86227761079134));
#867=CARTESIAN_POINT('',(22.1019289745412,2.6277643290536,1.78452995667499));
#868=CARTESIAN_POINT('',(22.186057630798,2.73001481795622,1.62379846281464));
#869=CARTESIAN_POINT('',(22.2273414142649,2.77773150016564,1.54081272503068));
#870=CARTESIAN_POINT('',(22.3067347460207,2.86587676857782,1.36988921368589));
#871=CARTESIAN_POINT('',(22.3448518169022,2.906322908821,1.2819640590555));
#872=CARTESIAN_POINT('',(22.4162226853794,2.97954955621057,1.10110231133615));
#873=CARTESIAN_POINT('',(22.449478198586,3.01233277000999,1.00816750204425));
#874=CARTESIAN_POINT('',(22.5157134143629,3.07595232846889,0.796207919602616));
#875=CARTESIAN_POINT('',(22.5469738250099,3.10471983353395,0.675990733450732));
#876=CARTESIAN_POINT('',(22.5949653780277,3.14815660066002,0.430371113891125));
#877=CARTESIAN_POINT('',(22.6117297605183,3.16285812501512,0.304981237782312));
#878=CARTESIAN_POINT('',(22.6279960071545,3.17713135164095,0.0514365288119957));
#879=CARTESIAN_POINT('',(22.6273998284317,3.1766171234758,-0.076729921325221));
#880=CARTESIAN_POINT('',(22.6088113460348,3.16028824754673,-0.330861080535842));
#881=CARTESIAN_POINT('',(22.5907978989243,3.14445500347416,-0.456822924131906));
#882=CARTESIAN_POINT('',(22.5353469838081,3.09409611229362,-0.727925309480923));
#883=CARTESIAN_POINT('',(22.4947228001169,3.05644259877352,-0.871805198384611));
#884=CARTESIAN_POINT('',(22.3998898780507,2.96340093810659,-1.1490818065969));
#885=CARTESIAN_POINT('',(22.3456466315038,2.90796763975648,-1.28245074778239));
#886=CARTESIAN_POINT('',(22.2483862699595,2.80156962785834,-1.4970753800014));
#887=CARTESIAN_POINT('',(22.2073119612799,2.75482579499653,-1.58137766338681));
#888=CARTESIAN_POINT('',(22.1233043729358,2.65435074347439,-1.74477765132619));
#889=CARTESIAN_POINT('',(22.0803705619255,2.60061751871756,-1.82387385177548));
#890=CARTESIAN_POINT('',(21.9939581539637,2.4863719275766,-1.97678903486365));
#891=CARTESIAN_POINT('',(21.9504791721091,2.42585450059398,-2.05060400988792));
#892=CARTESIAN_POINT('',(21.8641592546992,2.29821572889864,-2.19270371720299));
#893=CARTESIAN_POINT('',(21.8213183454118,2.23109411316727,-2.26098822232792));
#894=CARTESIAN_POINT('',(21.736909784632,2.08965312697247,-2.39235941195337));
#895=CARTESIAN_POINT('',(21.6953595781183,2.01526732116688,-2.45538597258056));
#896=CARTESIAN_POINT('',(21.6150514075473,1.86006134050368,-2.57495474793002));
#897=CARTESIAN_POINT('',(21.5762929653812,1.77924227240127,-2.63149807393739));
#898=CARTESIAN_POINT('',(21.5026577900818,1.61155622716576,-2.73739246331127));
#899=CARTESIAN_POINT('',(21.4677742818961,1.52470025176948,-2.78675612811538));
#900=CARTESIAN_POINT('',(21.4028504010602,1.34533858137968,-2.8776394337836));
#901=CARTESIAN_POINT('',(21.372807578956,1.25283577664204,-2.91916304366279));
#902=CARTESIAN_POINT('',(21.3072251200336,1.02309968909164,-3.00910606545));
#903=CARTESIAN_POINT('',(21.2745912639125,0.883255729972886,-3.05321763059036));
#904=CARTESIAN_POINT('',(21.236280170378,0.668420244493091,-3.10471922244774));
#905=CARTESIAN_POINT('',(21.225287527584,0.596021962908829,-3.11943634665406));
#906=CARTESIAN_POINT('',(21.2070296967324,0.449922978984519,-3.14382951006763));
#907=CARTESIAN_POINT('',(21.1997627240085,0.376222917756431,-3.15350796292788));
#908=CARTESIAN_POINT('',(21.1908385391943,0.252029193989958,-3.16538232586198));
#909=CARTESIAN_POINT('',(21.1881271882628,0.201738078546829,-3.16898581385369));
#910=CARTESIAN_POINT('',(21.1845075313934,0.100966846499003,-3.17379510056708));
#911=CARTESIAN_POINT('',(21.1835995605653,0.0504866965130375,-3.17500045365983));
#912=CARTESIAN_POINT('',(21.1836,0.,-3.17499999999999));
#913=B_SPLINE_CURVE_WITH_KNOTS('',3,(#797,#798,#799,#800,#801,#802,#803,#804,#805,#806,#807,
#808,#809,#810,#811,#812,#813,#814,#815,#816,#817,#818,#819,#820,#821,#822,#823,#824,#825,#826,
#827,#828,#829,#830,#831,#832,#833,#834,#835,#836,#837,#838,#839,#840,#841,#842,#843,#844,#845,
#846,#847,#848,#849,#850,#851,#852,#853,#854,#855,#856,#857,#858,#859,#860,#861,#862,#863,#864,
#865,#866,#867,#868,#869,#870,#871,#872,#873,#874,#875,#876,#877,#878,#879,#880,#881,#882,#883,
#884,#885,#886,#887,#888,#889,#890,#891,#892,#893,#894,#895,#896,#897,#898,#899,#900,#901,#902,
#903,#904,#905,#906,#907,#908,#909,#910,#911,#912),.UNSPECIFIED.,.T.,.F.,(4,2,2,2,2,2,2,2,2,2,2,
2,2,2,2,2,2,2,2,2,2,2,2,2,2,2,2,2,2,2,2,2,2,2,2,2,2,2,2,2,2,2,2,2,2,2,2,2,2,2,2,2,2,2,2,2,2,4),
(0.,0.232337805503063,0.464805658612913,0.69768860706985,0.930675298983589,1.3933156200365,
1.85583957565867,2.36128044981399,2.86750060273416,3.17265873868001,3.47790925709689,
3.78279828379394,4.08763729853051,4.48632228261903,4.88408383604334,5.28551162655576,
5.68706856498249,6.0446052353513,6.40249225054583,6.98604030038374,7.57102930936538,
8.17136906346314,8.77055907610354,9.25104012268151,9.73122357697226,9.97313338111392,
10.2149319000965,10.4566998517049,10.6984479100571,11.1317076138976,11.5650568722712,
12.0125413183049,12.4600890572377,12.9820369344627,13.5051248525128,13.8173634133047,
14.1297157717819,14.4413035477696,14.7527810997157,15.1338010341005,15.5139449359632,
15.8962360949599,16.2789919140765,16.7390040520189,17.2001937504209,17.5141831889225,
17.8282629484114,18.1425785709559,18.456907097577,18.7744418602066,19.0919221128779,
19.4088382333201,19.7255934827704,20.1740110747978,20.3978707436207,20.621623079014,
20.7730195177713,20.9244440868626),.UNSPECIFIED.);
#914=CARTESIAN_POINT('',(21.1836,0.,-3.17499999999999));
#915=VERTEX_POINT('',#914);
#916=EDGE_CURVE('E197',#915,#915,#913,.T.);
#917=ORIENTED_EDGE('',*,*,#916,.T.);
#918=EDGE_LOOP('',(#917));
#919=FACE_BOUND('',#918,.T.);
#920=ORIENTED_EDGE('',*,*,#591,.T.);
#921=CARTESIAN_POINT('',(25.4,0.,4.18846));
#922=DIRECTION('',(0.,0.,1.));
#923=DIRECTION('',(1.,0.,0.));
#924=AXIS2_PLACEMENT_3D('',#921,#922,#923);
#925=CIRCLE('',#924,4.2164);
#926=EDGE_CURVE('E56',#549,#506,#925,.T.);
#927=ORIENTED_EDGE('',*,*,#926,.T.);
#928=ORIENTED_EDGE('',*,*,#507,.T.);
#929=ORIENTED_EDGE('',*,*,#604,.T.);
#930=ORIENTED_EDGE('',*,*,#462,.T.);
#931=ORIENTED_EDGE('',*,*,#32,.T.);
#932=EDGE_LOOP('',(#920,#927,#928,#929,#930,#931));
#933=FACE_BOUND('',#932,.T.);
#934=ORIENTED_EDGE('',*,*,#787,.F.);
#935=EDGE_LOOP('',(#934));
#936=FACE_BOUND('',#935,.T.);
#937=ADVANCED_FACE('F174',(#919,#933,#936),#796,.F.);
#938=CARTESIAN_POINT('',(29.6164,0.,4.18846));
#939=DIRECTION('',(0.,0.,-1.));
#940=DIRECTION('',(-1.,0.,0.));
#941=AXIS2_PLACEMENT_3D('',#938,#939,#940);
#942=PLANE('',#941);
#943=ORIENTED_EDGE('',*,*,#515,.T.);
#944=ORIENTED_EDGE('',*,*,#926,.F.);
#945=ORIENTED_EDGE('',*,*,#550,.T.);
#946=CARTESIAN_POINT('',(25.4,0.,4.18846));
#947=DIRECTION('',(0.,0.,1.));
#948=DIRECTION('',(1.,0.,0.));
#949=AXIS2_PLACEMENT_3D('',#946,#947,#948);
#950=CIRCLE('',#949,4.93618496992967);
#951=EDGE_CURVE('E257',#541,#514,#950,.T.);
#952=ORIENTED_EDGE('',*,*,#951,.T.);
#953=EDGE_LOOP('',(#943,#944,#945,#952));
#954=FACE_BOUND('',#953,.T.);
#955=ADVANCED_FACE('F179',(#954),#942,.F.);
#956=CARTESIAN_POINT('',(25.4,0.,11.1125));
#957=DIRECTION('',(0.,0.,1.));
#958=DIRECTION('',(1.,0.,0.));
#959=AXIS2_PLACEMENT_3D('',#956,#957,#958);
#960=CONICAL_SURFACE('',#959,5.1435,0.0299323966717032);
#961=ORIENTED_EDGE('',*,*,#542,.T.);
#962=ORIENTED_EDGE('',*,*,#951,.F.);
#963=EDGE_LOOP('',(#961,#962));
#964=FACE_BOUND('',#963,.T.);
#965=ORIENTED_EDGE('',*,*,#193,.T.);
#966=EDGE_LOOP('',(#965));
#967=FACE_BOUND('',#966,.T.);
#968=ADVANCED_FACE('F223',(#964,#967),#960,.F.);
#969=CARTESIAN_POINT('',(12.3444,0.,4.18846));
#970=DIRECTION('',(0.,0.,-1.));
#971=DIRECTION('',(-1.,0.,0.));
#972=AXIS2_PLACEMENT_3D('',#969,#970,#971);
#973=PLANE('',#972);
#974=ORIENTED_EDGE('',*,*,#723,.F.);
#975=EDGE_LOOP('',(#974));
#976=FACE_BOUND('',#975,.T.);
#977=CARTESIAN_POINT('',(8.128,0.,4.18846));
#978=DIRECTION('',(0.,0.,1.));
#979=DIRECTION('',(1.,0.,0.));
#980=AXIS2_PLACEMENT_3D('',#977,#978,#979);
#981=CIRCLE('',#980,4.93618496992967);
#982=CARTESIAN_POINT('',(13.0641849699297,0.,4.18846));
#983=VERTEX_POINT('',#982);
#984=EDGE_CURVE('E560',#983,#983,#981,.T.);
#985=ORIENTED_EDGE('',*,*,#984,.T.);
#986=EDGE_LOOP('',(#985));
#987=FACE_BOUND('',#986,.T.);
#988=ADVANCED_FACE('F220',(#976,#987),#973,.F.);
#989=CARTESIAN_POINT('',(8.128,0.,11.1125));
#990=DIRECTION('',(0.,0.,1.));
#991=DIRECTION('',(1.,0.,0.));
#992=AXIS2_PLACEMENT_3D('',#989,#990,#991);
#993=CONICAL_SURFACE('',#992,5.1435,0.0299323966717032);
#994=ORIENTED_EDGE('',*,*,#984,.F.);
#995=EDGE_LOOP('',(#994));
#996=FACE_BOUND('',#995,.T.);
#997=ORIENTED_EDGE('',*,*,#182,.T.);
#998=EDGE_LOOP('',(#997));
#999=FACE_BOUND('',#998,.T.);
#1000=ADVANCED_FACE('F216',(#996,#999),#993,.F.);
#1001=CARTESIAN_POINT('',(41.275,0.,0.));
#1002=DIRECTION('',(1.,0.,0.));
#1003=DIRECTION('',(0.,0.,-1.));
#1004=AXIS2_PLACEMENT_3D('',#1001,#1002,#1003);
#1005=CYLINDRICAL_SURFACE('',#1004,2.70509999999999);
#1006=CARTESIAN_POINT('',(14.351,0.,0.));
#1007=DIRECTION('',(1.,0.,0.));
#1008=DIRECTION('',(0.,0.,-1.));
#1009=AXIS2_PLACEMENT_3D('',#1006,#1007,#1008);
#1010=CIRCLE('',#1009,2.70509999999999);
#1011=CARTESIAN_POINT('',(14.351,0.,-2.70509999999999));
#1012=VERTEX_POINT('',#1011);
#1013=EDGE_CURVE('E203',#1012,#1012,#1010,.T.);
#1014=ORIENTED_EDGE('',*,*,#1013,.T.);
#1015=EDGE_LOOP('',(#1014));
#1016=FACE_BOUND('',#1015,.T.);
#1017=ORIENTED_EDGE('',*,*,#712,.F.);
#1018=EDGE_LOOP('',(#1017));
#1019=FACE_BOUND('',#1018,.T.);
#1020=ADVANCED_FACE('F209',(#1016,#1019),#1005,.F.);
#1021=CARTESIAN_POINT('',(41.275,0.,0.));
#1022=DIRECTION('',(1.,0.,0.));
#1023=DIRECTION('',(0.,0.,-1.));
#1024=AXIS2_PLACEMENT_3D('',#1021,#1022,#1023);
#1025=CYLINDRICAL_SURFACE('',#1024,3.175);
#1026=CARTESIAN_POINT('',(14.351,0.,0.));
#1027=DIRECTION('',(1.,0.,0.));
#1028=DIRECTION('',(0.,0.,-1.));
#1029=AXIS2_PLACEMENT_3D('',#1026,#1027,#1028);
#1030=CIRCLE('',#1029,3.17499999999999);
#1031=CARTESIAN_POINT('',(14.351,0.,-3.17499999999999));
#1032=VERTEX_POINT('',#1031);
#1033=EDGE_CURVE('E569',#1032,#1032,#1030,.T.);
#1034=ORIENTED_EDGE('',*,*,#1033,.F.);
#1035=EDGE_LOOP('',(#1034));
#1036=FACE_BOUND('',#1035,.T.);
#1037=ORIENTED_EDGE('',*,*,#916,.F.);
#1038=EDGE_LOOP('',(#1037));
#1039=FACE_BOUND('',#1038,.T.);
#1040=ADVANCED_FACE('F204',(#1036,#1039),#1025,.F.);
#1041=CARTESIAN_POINT('',(14.351,2.70509999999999,0.));
#1042=DIRECTION('',(-1.,0.,0.));
#1043=DIRECTION('',(0.,0.,1.));
#1044=AXIS2_PLACEMENT_3D('',#1041,#1042,#1043);
#1045=PLANE('',#1044);
#1046=ORIENTED_EDGE('',*,*,#1013,.F.);
#1047=EDGE_LOOP('',(#1046));
#1048=FACE_BOUND('',#1047,.T.);
#1049=ORIENTED_EDGE('',*,*,#1033,.T.);
#1050=EDGE_LOOP('',(#1049));
#1051=FACE_BOUND('',#1050,.T.);
#1052=ADVANCED_FACE('F208',(#1048,#1051),#1045,.F.);
#1053=CLOSED_SHELL('',(#43,#71,#138,#169,#215,#239,#263,#298,#315,#329,#341,#361,#381,#599,#609,
#738,#758,#770,#791,#937,#955,#968,#988,#1000,#1020,#1040,#1052));
#1054=MANIFOLD_SOLID_BREP('B2',#1053);
#1055=ADVANCED_BREP_SHAPE_REPRESENTATION('',(#18,#1054),#14);
#1056=SHAPE_DEFINITION_REPRESENTATION(#9,#1055);
ENDSEC;
END-ISO-10303-21;
